VERSION 5.8 ;
BUSBITCHARS "[]" ;
DIVIDERCHAR "/" ;
UNITS
    DATABASE MICRONS 1000 ;
END UNITS

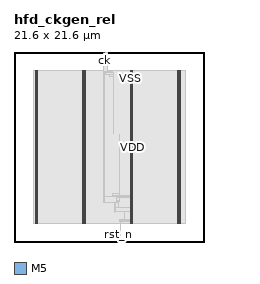
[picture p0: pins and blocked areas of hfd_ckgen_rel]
MACRO hfd_ckgen_rel
  FOREIGN hfd_ckgen_rel 0 0 ;
  CLASS BLOCK ;
  SIZE 21.6 BY 21.6 ;
  PIN ck
    DIRECTION INPUT ;
    USE SIGNAL ;
    PORT
      LAYER M5 ;
        RECT  10.224 21.516 10.248 21.6 ;
    END
  END ck
  PIN locked
    DIRECTION INPUT ;
    USE SIGNAL ;
    PORT
      LAYER M5 ;
        RECT  10.32 21.516 10.344 21.6 ;
    END
  END locked
  PIN por_n
    DIRECTION INPUT ;
    USE SIGNAL ;
    PORT
      LAYER M5 ;
        RECT  10.416 21.516 10.44 21.6 ;
    END
  END por_n
  PIN rst_n
    DIRECTION OUTPUT ;
    USE SIGNAL ;
    PORT
      LAYER M5 ;
        RECT  11.856 0 11.88 0.084 ;
    END
    PORT
      LAYER M5 ;
        RECT  11.856 0.016 11.88 0.037 ;
    END
    PORT
      LAYER M5 ;
        RECT  11.856 0.037 11.976 0.179 ;
    END
  END rst_n
  PIN VDD
    DIRECTION INOUT ;
    USE POWER ;
    PORT
      LAYER M5 ;
        RECT  18.792 2.151 18.912 19.449 ;
        RECT  13.392 2.151 13.512 19.449 ;
        RECT  7.992 2.151 8.112 19.449 ;
        RECT  2.592 2.151 2.712 19.449 ;
    END
  END VDD
  PIN VSS
    DIRECTION INOUT ;
    USE GROUND ;
    PORT
      LAYER M5 ;
        RECT  18.6 2.137 18.72 19.463 ;
        RECT  13.2 2.137 13.32 19.463 ;
        RECT  7.8 2.137 7.92 19.463 ;
        RECT  2.4 2.137 2.52 19.463 ;
    END
  END VSS
  # OT_OBS_CLOSED layer=M5 d_um=1.536 added=2
  OBS
    LAYER RVTN ;
     RECT  2.16 2.16 19.44 2.295 ;
     RECT  2.16 2.565 19.44 2.835 ;
     RECT  2.16 3.105 19.44 3.375 ;
     RECT  2.16 3.645 19.44 3.915 ;
     RECT  2.16 4.185 19.44 4.455 ;
     RECT  2.16 4.725 19.44 4.995 ;
     RECT  2.16 5.265 19.44 5.535 ;
     RECT  2.16 5.805 19.44 6.075 ;
     RECT  2.16 6.345 19.44 6.615 ;
     RECT  2.16 6.885 19.44 7.155 ;
     RECT  2.16 7.425 19.44 7.695 ;
     RECT  2.16 7.965 19.44 8.235 ;
     RECT  2.16 8.505 19.44 8.775 ;
     RECT  2.16 9.045 19.44 9.315 ;
     RECT  2.16 9.585 19.44 9.855 ;
     RECT  2.16 10.125 19.44 10.395 ;
     RECT  2.16 10.665 19.44 10.935 ;
     RECT  2.16 11.205 19.44 11.475 ;
     RECT  2.16 11.745 19.44 12.015 ;
     RECT  2.16 12.285 19.44 12.555 ;
     RECT  2.16 12.825 19.44 13.095 ;
     RECT  2.16 13.365 19.44 13.635 ;
     RECT  2.16 13.905 19.44 14.175 ;
     RECT  2.16 14.445 19.44 14.715 ;
     RECT  2.16 14.985 19.44 15.255 ;
     RECT  2.16 15.525 19.44 15.795 ;
     RECT  2.16 16.065 19.44 16.335 ;
     RECT  2.16 16.605 19.44 16.875 ;
     RECT  2.16 17.145 19.44 17.415 ;
     RECT  2.16 17.685 19.44 17.955 ;
     RECT  2.16 18.225 19.44 18.495 ;
     RECT  2.16 18.765 19.44 19.035 ;
     RECT  2.16 19.305 19.44 19.44 ;
    LAYER RVTP ;
     RECT  2.16 2.295 19.44 2.565 ;
     RECT  2.16 2.835 19.44 3.105 ;
     RECT  2.16 3.375 19.44 3.645 ;
     RECT  2.16 3.915 19.44 4.185 ;
     RECT  2.16 4.455 19.44 4.725 ;
     RECT  2.16 4.995 19.44 5.265 ;
     RECT  2.16 5.535 19.44 5.805 ;
     RECT  2.16 6.075 19.44 6.345 ;
     RECT  2.16 6.615 19.44 6.885 ;
     RECT  2.16 7.155 19.44 7.425 ;
     RECT  2.16 7.695 19.44 7.965 ;
     RECT  2.16 8.235 19.44 8.505 ;
     RECT  2.16 8.775 19.44 9.045 ;
     RECT  2.16 9.315 19.44 9.585 ;
     RECT  2.16 9.855 19.44 10.125 ;
     RECT  2.16 10.395 19.44 10.665 ;
     RECT  2.16 10.935 19.44 11.205 ;
     RECT  2.16 11.475 19.44 11.745 ;
     RECT  2.16 12.015 19.44 12.285 ;
     RECT  2.16 12.555 19.44 12.825 ;
     RECT  2.16 13.095 19.44 13.365 ;
     RECT  2.16 13.635 19.44 13.905 ;
     RECT  2.16 14.175 19.44 14.445 ;
     RECT  2.16 14.715 19.44 14.985 ;
     RECT  2.16 15.255 19.44 15.525 ;
     RECT  2.16 15.795 19.44 16.065 ;
     RECT  2.16 16.335 19.44 16.605 ;
     RECT  2.16 16.875 19.44 17.145 ;
     RECT  2.16 17.415 19.44 17.685 ;
     RECT  2.16 17.955 19.44 18.225 ;
     RECT  2.16 18.495 19.44 18.765 ;
     RECT  2.16 19.035 19.44 19.305 ;
    LAYER M1 ;
     RECT  2.16 2.151 19.44 19.449 ;
    LAYER M2 ;
     RECT  2.16 2.151 19.44 19.449 ;
    LAYER M3 ;
     RECT  12.132 0.043 12.15 2.335 ;
     RECT  13.215 2.143 13.305 2.335 ;
     RECT  12.132 2.335 13.305 2.371 ;
     RECT  2.415 2.143 2.505 2.413 ;
     RECT  7.815 2.143 7.905 2.413 ;
     RECT  12.024 2.371 13.305 2.413 ;
     RECT  18.615 2.143 18.705 2.413 ;
     RECT  12.024 2.413 13.497 2.525 ;
     RECT  11.412 3.379 11.43 3.437 ;
     RECT  12.6 2.525 13.497 3.451 ;
     RECT  11.52 3.451 13.497 3.875 ;
     RECT  11.52 3.875 11.934 4.495 ;
     RECT  11.304 4.495 11.934 4.621 ;
     RECT  11.304 4.621 11.97 4.765 ;
     RECT  11.304 4.765 12.042 5.071 ;
     RECT  13.215 3.875 13.497 5.071 ;
     RECT  11.268 5.071 13.497 5.131 ;
     RECT  11.16 5.131 13.497 5.261 ;
     RECT  11.16 5.261 11.97 5.459 ;
     RECT  11.16 5.459 11.178 5.495 ;
     RECT  11.952 5.459 11.97 12.209 ;
     RECT  11.34 12.325 11.358 18.769 ;
     RECT  10.872 18.769 11.358 19.075 ;
     RECT  2.415 2.413 2.697 19.187 ;
     RECT  7.815 2.413 8.097 19.187 ;
     RECT  13.215 5.261 13.497 19.187 ;
     RECT  18.615 2.413 18.897 19.187 ;
     RECT  10.404 19.075 11.358 19.229 ;
     RECT  10.404 19.229 11.178 19.336 ;
     RECT  10.296 19.336 11.178 19.337 ;
     RECT  10.296 19.337 10.566 19.373 ;
     RECT  10.548 19.373 10.566 19.379 ;
     RECT  2.415 19.187 2.505 19.457 ;
     RECT  7.815 19.187 7.905 19.457 ;
     RECT  13.215 19.187 13.305 19.457 ;
     RECT  18.615 19.187 18.705 19.457 ;
    LAYER M4 ;
     RECT  2.408 2.148 2.512 19.452 ;
     RECT  2.512 2.418 2.704 19.182 ;
     RECT  7.808 2.148 7.912 19.452 ;
     RECT  7.912 2.418 8.104 19.182 ;
     RECT  10.285 19.344 10.595 19.368 ;
     RECT  10.405 21.456 10.595 21.48 ;
     RECT  10.213 4.512 11.149 4.536 ;
     RECT  11.372 3.408 11.459 3.432 ;
     RECT  11.149 4.512 11.651 5.16 ;
     RECT  11.651 4.512 11.692 4.536 ;
     RECT  11.845 0.144 11.886 0.168 ;
     RECT  11.886 0.048 11.987 0.168 ;
     RECT  11.987 0.048 12.161 0.072 ;
     RECT  13.208 2.148 13.312 19.452 ;
     RECT  13.312 2.418 13.504 19.182 ;
     RECT  18.608 2.148 18.712 19.452 ;
     RECT  18.712 2.418 18.904 19.182 ;
    LAYER M5 ;
     RECT  2.4 2.137 2.52 2.151 ;
     RECT  7.8 2.137 7.92 2.151 ;
     RECT  13.2 2.137 13.32 2.151 ;
     RECT  18.6 2.137 18.72 2.151 ;
     RECT  11.424 3.397 11.448 4.501 ;
     RECT  11.424 4.501 11.64 4.547 ;
     RECT  11.616 4.547 11.64 5.171 ;
     RECT  10.224 4.501 10.248 19.333 ;
     RECT  2.4 2.151 2.712 19.449 ;
     RECT  7.8 2.151 8.112 19.449 ;
     RECT  13.2 2.151 13.512 19.449 ;
     RECT  18.6 2.151 18.912 19.449 ;
     RECT  2.4 19.449 2.52 19.463 ;
     RECT  7.8 19.449 7.92 19.463 ;
     RECT  13.2 19.449 13.32 19.463 ;
     RECT  18.6 19.449 18.72 19.463 ;
     RECT  10.224 19.333 10.584 21.491 ;
     RECT  10.224 21.491 10.44 21.584 ;
     RECT  10.248 4.501 11.424 4.547 ;
     RECT  10.248 4.547 11.616 5.171 ;
  END
END hfd_ckgen_rel
END LIBRARY
